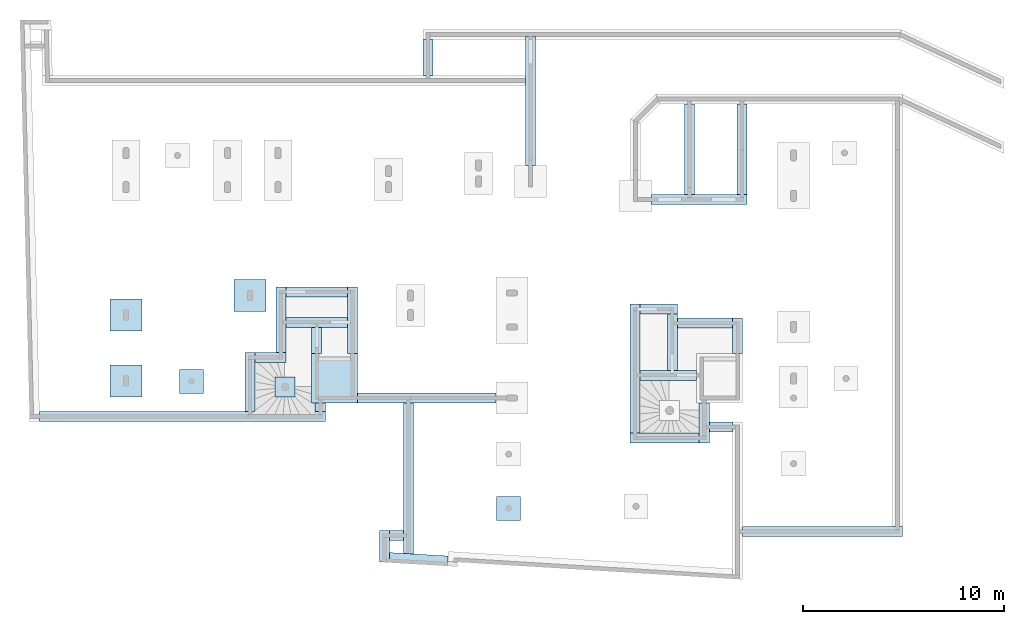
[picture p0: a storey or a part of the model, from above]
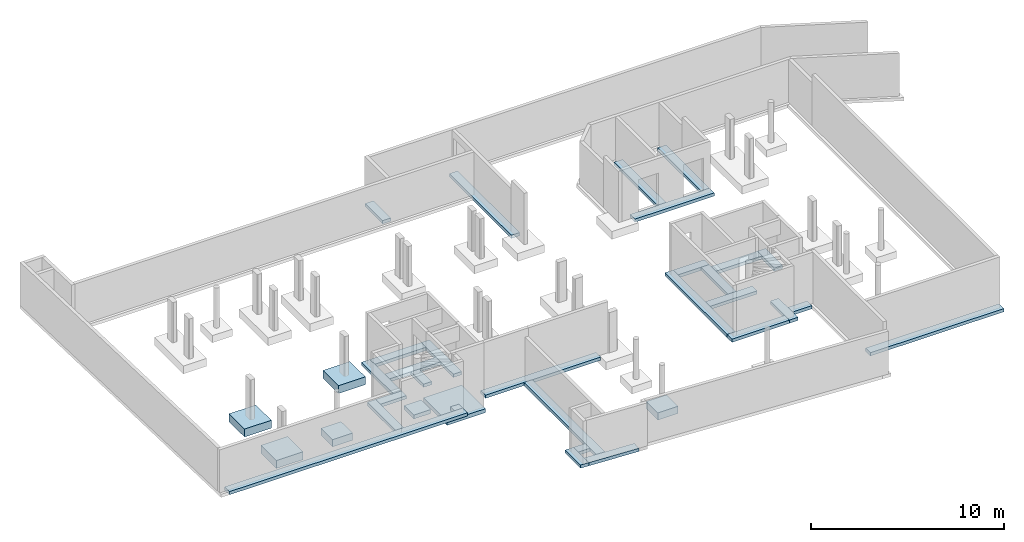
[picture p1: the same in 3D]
Properties of the parts of a building model (IFC2X3)

# File
Description: ViewDefinition [CoordinationView_V2.0]
File name: D:\Documents\Cours 2016-2017\dossier bac pro\sous sol.ifc
Time: 2017-04-04T10:15:29
Organization: Nemetschek AG, Konrad-Zuse-Platz 1, 81829 Munich / Germany
Written by: The EXPRESS Data Manager Version 5.02.0110.b05 : 16 Jul 2014
Made in: Allplan 2016.1 29.11.2016 - 13:12:12

# IfcBuildingStorey, Sous-sol
In: Bâtiment
Elevation: -3300 mm

# IfcColumn (33)
In: Sous-sol
Material: <Unnamed Material>
Allplan Attributes - Catégorie de transformation: Nouvelle construction; Unité: m; Métier: Béton et béton armé
Name | Id_élt_Allmétré | NOI_UUID
<Unnamed Element> | 0022Pot0000001171 | a5af95d6-19c8-4933-9c63-25be082ca570--1171
<Unnamed Element> | 0022Pot0000001170 | a5af95d6-19c8-4933-9c63-25be082ca570--1170
<Unnamed Element> | 0022Pot0000001088 | a5af95d6-19c8-4933-9c63-25be082ca570--1088
<Unnamed Element> | 0022Pot0000001085 | a5af95d6-19c8-4933-9c63-25be082ca570--1085
<Unnamed Element> | 0022Pot0000001082 | a5af95d6-19c8-4933-9c63-25be082ca570--1082
<Unnamed Element> | 0022Pot0000001079 | a5af95d6-19c8-4933-9c63-25be082ca570--1079
<Unnamed Element> | 0022Pot0000001076 | a5af95d6-19c8-4933-9c63-25be082ca570--1076
<Unnamed Element> | 0022Pot0000001073 | a5af95d6-19c8-4933-9c63-25be082ca570--1073
<Unnamed Element> | 0022Pot0000001072 | a5af95d6-19c8-4933-9c63-25be082ca570--1072
<Unnamed Element> | 0022Pot0000001071 | a5af95d6-19c8-4933-9c63-25be082ca570--1071
<Unnamed Element> | 0022Pot0000001066 | a5af95d6-19c8-4933-9c63-25be082ca570--1066
<Unnamed Element> | 0022Pot0000001065 | a5af95d6-19c8-4933-9c63-25be082ca570--1065
<Unnamed Element> | 0022Pot0000001064 | a5af95d6-19c8-4933-9c63-25be082ca570--1064
<Unnamed Element> | 0022Pot0000001063 | a5af95d6-19c8-4933-9c63-25be082ca570--1063
<Unnamed Element> | 0022Pot0000001062 | a5af95d6-19c8-4933-9c63-25be082ca570--1062
<Unnamed Element> | 0022Pot0000001061 | a5af95d6-19c8-4933-9c63-25be082ca570--1061
<Unnamed Element> | 0022Pot0000001060 | a5af95d6-19c8-4933-9c63-25be082ca570--1060
<Unnamed Element> | 0022Pot0000001059 | a5af95d6-19c8-4933-9c63-25be082ca570--1059
<Unnamed Element> | 0022Pot0000001058 | a5af95d6-19c8-4933-9c63-25be082ca570--1058
<Unnamed Element> | 0022Pot0000001057 | a5af95d6-19c8-4933-9c63-25be082ca570--1057
<Unnamed Element> | 0022Pot0000001056 | a5af95d6-19c8-4933-9c63-25be082ca570--1056
<Unnamed Element> | 0022Pot0000001055 | a5af95d6-19c8-4933-9c63-25be082ca570--1055
<Unnamed Element> | 0022Pot0000001054 | a5af95d6-19c8-4933-9c63-25be082ca570--1054
<Unnamed Element> | 0022Pot0000001053 | a5af95d6-19c8-4933-9c63-25be082ca570--1053
<Unnamed Element> | 0022Pot0000001052 | a5af95d6-19c8-4933-9c63-25be082ca570--1052
<Unnamed Element> | 0022Pot0000001051 | a5af95d6-19c8-4933-9c63-25be082ca570--1051
<Unnamed Element> | 0022Pot0000001050 | a5af95d6-19c8-4933-9c63-25be082ca570--1050
<Unnamed Element> | 0022Pot0000001049 | a5af95d6-19c8-4933-9c63-25be082ca570--1049
<Unnamed Element> | 0022Pot0000001048 | a5af95d6-19c8-4933-9c63-25be082ca570--1048
<Unnamed Element> | 0022Pot0000001045 | a5af95d6-19c8-4933-9c63-25be082ca570--1045
<Unnamed Element> | 0022Pot0000003037 | a5af95d6-19c8-4933-9c63-25be082ca570--3037
<Unnamed Element> | 0022Pot0000003062 | a5af95d6-19c8-4933-9c63-25be082ca570--3062
<Unnamed Element> | 0022Pot0000003086 | a5af95d6-19c8-4933-9c63-25be082ca570--3086

# IfcFooting (72)
In: Sous-sol
Material: <Unnamed Material>
Allplan Attributes - Catégorie de transformation: Nouvelle construction
Name | Id_élt_Allmétré | Unité | NOI_UUID | PredefinedType
<Unnamed Element> | 0022SeI0000001096 | m³ | a5af95d6-19c8-4933-9c63-25be082ca570--1096
<Unnamed Element> | 0022SeI0000001104 | m³ | a5af95d6-19c8-4933-9c63-25be082ca570--1104
<Unnamed Element> | 0022SeI0000001106 | m³ | a5af95d6-19c8-4933-9c63-25be082ca570--1106
<Unnamed Element> | 0022SeI0000001108 | m³ | a5af95d6-19c8-4933-9c63-25be082ca570--1108
<Unnamed Element> | 0022SeI0000001117 | m³ | a5af95d6-19c8-4933-9c63-25be082ca570--1117
<Unnamed Element> | 0022SeI0000001125 | m³ | a5af95d6-19c8-4933-9c63-25be082ca570--1125
<Unnamed Element> | 0022SeI0000001126 | m³ | a5af95d6-19c8-4933-9c63-25be082ca570--1126
<Unnamed Element> | 0022SeI0000001127 | m³ | a5af95d6-19c8-4933-9c63-25be082ca570--1127
<Unnamed Element> | 0022SeI0000001135 | m³ | a5af95d6-19c8-4933-9c63-25be082ca570--1135
<Unnamed Element> | 0022SeI0000001136 | m³ | a5af95d6-19c8-4933-9c63-25be082ca570--1136
<Unnamed Element> | 0022SeI0000001137 | m³ | a5af95d6-19c8-4933-9c63-25be082ca570--1137
<Unnamed Element> | 0022SeI0000001138 | m³ | a5af95d6-19c8-4933-9c63-25be082ca570--1138
<Unnamed Element> | 0022SeI0000001107 | m³ | a5af95d6-19c8-4933-9c63-25be082ca570--1107
<Unnamed Element> | 0022SeI0000001147 | m³ | a5af95d6-19c8-4933-9c63-25be082ca570--1147
<Unnamed Element> | 0022SeI0000001148 | m³ | a5af95d6-19c8-4933-9c63-25be082ca570--1148
<Unnamed Element> | 0022SeI0000001149 | m³ | a5af95d6-19c8-4933-9c63-25be082ca570--1149
<Unnamed Element> | 0022SeI0000001150 | m³ | a5af95d6-19c8-4933-9c63-25be082ca570--1150
<Unnamed Element> | 0022SeI0000001151 | m³ | a5af95d6-19c8-4933-9c63-25be082ca570--1151
<Unnamed Element> | 0022SeI0000001152 | m³ | a5af95d6-19c8-4933-9c63-25be082ca570--1152
<Unnamed Element> | 0022SeI0000001153 | m³ | a5af95d6-19c8-4933-9c63-25be082ca570--1153
<Unnamed Element> | 0022SeI0000001154 | m³ | a5af95d6-19c8-4933-9c63-25be082ca570--1154
<Unnamed Element> | 0022SeI0000001155 | m³ | a5af95d6-19c8-4933-9c63-25be082ca570--1155
<Unnamed Element> | 0022SeI0000001172 | m³ | a5af95d6-19c8-4933-9c63-25be082ca570--1172
<Unnamed Element> | 0022SeI0000001182 | m³ | a5af95d6-19c8-4933-9c63-25be082ca570--1182
<Unnamed Element> | 0022SeI0000001183 | m³ | a5af95d6-19c8-4933-9c63-25be082ca570--1183
<Unnamed Element> | 0022SeF0000001484 | m³ | a5af95d6-19c8-4933-9c63-25be082ca570--1484 | STRIP_FOOTING
<Unnamed Element> | 0022SeF0000001908 | m³ | a5af95d6-19c8-4933-9c63-25be082ca570--1908 | STRIP_FOOTING
<Unnamed Element> | 0022SeF0000001926 | m³ | a5af95d6-19c8-4933-9c63-25be082ca570--1926 | STRIP_FOOTING
<Unnamed Element> | 0022SeF0000001776 | m³ | a5af95d6-19c8-4933-9c63-25be082ca570--1776 | STRIP_FOOTING
<Unnamed Element> | 0022SeF0000001761 | m³ | a5af95d6-19c8-4933-9c63-25be082ca570--1761 | STRIP_FOOTING
<Unnamed Element> | 0022SeF0000001765 | m³ | a5af95d6-19c8-4933-9c63-25be082ca570--1765 | STRIP_FOOTING
<Unnamed Element> | 0022SeF0000001983 | m³ | a5af95d6-19c8-4933-9c63-25be082ca570--1983 | STRIP_FOOTING
<Unnamed Element> | 0022SeF0000001684 | m³ | a5af95d6-19c8-4933-9c63-25be082ca570--1684 | STRIP_FOOTING
<Unnamed Element> | 0022SeF0000001894 | m³ | a5af95d6-19c8-4933-9c63-25be082ca570--1894 | STRIP_FOOTING
<Unnamed Element> | 0022SeF0000002163 | m³ | a5af95d6-19c8-4933-9c63-25be082ca570--2163 | STRIP_FOOTING
<Unnamed Element> | 0022SeF0000002172 | m³ | a5af95d6-19c8-4933-9c63-25be082ca570--2172 | STRIP_FOOTING
<Unnamed Element> | 0022Rad0000002350 | m² | a5af95d6-19c8-4933-9c63-25be082ca570--2350
<Unnamed Element> | 0022Rad0000002353 | m² | a5af95d6-19c8-4933-9c63-25be082ca570--2353
<Unnamed Element> | 0022SeF0000002139 | m³ | a5af95d6-19c8-4933-9c63-25be082ca570--2139 | STRIP_FOOTING
<Unnamed Element> | 0022SeF0000002156 | m³ | a5af95d6-19c8-4933-9c63-25be082ca570--2156 | STRIP_FOOTING
<Unnamed Element> | 0022SeF0000002149 | m³ | a5af95d6-19c8-4933-9c63-25be082ca570--2149 | STRIP_FOOTING
<Unnamed Element> | 0022SeF0000002184 | m³ | a5af95d6-19c8-4933-9c63-25be082ca570--2184 | STRIP_FOOTING
<Unnamed Element> | 0022SeF0000002135 | m³ | a5af95d6-19c8-4933-9c63-25be082ca570--2135 | STRIP_FOOTING
<Unnamed Element> | 0022SeF0000002122 | m³ | a5af95d6-19c8-4933-9c63-25be082ca570--2122 | STRIP_FOOTING
<Unnamed Element> | 0022SeF0000001665 | m³ | a5af95d6-19c8-4933-9c63-25be082ca570--1665 | STRIP_FOOTING
<Unnamed Element> | 0022SeF0000001672 | m³ | a5af95d6-19c8-4933-9c63-25be082ca570--1672 | STRIP_FOOTING
<Unnamed Element> | 0022SeF0000001730 | m³ | a5af95d6-19c8-4933-9c63-25be082ca570--1730 | STRIP_FOOTING
<Unnamed Element> | 0022SeF0000001410 | m³ | a5af95d6-19c8-4933-9c63-25be082ca570--1410 | STRIP_FOOTING
<Unnamed Element> | 0022SeF0000001420 | m³ | a5af95d6-19c8-4933-9c63-25be082ca570--1420 | STRIP_FOOTING
<Unnamed Element> | 0022SeF0000001472 | m³ | a5af95d6-19c8-4933-9c63-25be082ca570--1472 | STRIP_FOOTING
<Unnamed Element> | 0022SeF0000001448 | m³ | a5af95d6-19c8-4933-9c63-25be082ca570--1448 | STRIP_FOOTING
<Unnamed Element> | 0022SeF0000001460 | m³ | a5af95d6-19c8-4933-9c63-25be082ca570--1460 | STRIP_FOOTING
<Unnamed Element> | 0022SeF0000001406 | m³ | a5af95d6-19c8-4933-9c63-25be082ca570--1406 | STRIP_FOOTING
<Unnamed Element> | 0022SeF0000002000 | m³ | a5af95d6-19c8-4933-9c63-25be082ca570--2000 | STRIP_FOOTING
<Unnamed Element> | 0022SeF0000001957 | m³ | a5af95d6-19c8-4933-9c63-25be082ca570--1957 | STRIP_FOOTING
<Unnamed Element> | 0022SeF0000001737 | m³ | a5af95d6-19c8-4933-9c63-25be082ca570--1737 | STRIP_FOOTING
<Unnamed Element> | 0022SeF0000001996 | m³ | a5af95d6-19c8-4933-9c63-25be082ca570--1996 | STRIP_FOOTING
<Unnamed Element> | 0022SeF0000001964 | m³ | a5af95d6-19c8-4933-9c63-25be082ca570--1964 | STRIP_FOOTING
<Unnamed Element> | 0022SeF0000001749 | m³ | a5af95d6-19c8-4933-9c63-25be082ca570--1749 | STRIP_FOOTING
<Unnamed Element> | 0022SeF0000002013 | m³ | a5af95d6-19c8-4933-9c63-25be082ca570--2013 | STRIP_FOOTING
<Unnamed Element> | 0022SeF0000002053 | m³ | a5af95d6-19c8-4933-9c63-25be082ca570--2053 | STRIP_FOOTING
<Unnamed Element> | 0022SeF0000001708 | m³ | a5af95d6-19c8-4933-9c63-25be082ca570--1708 | STRIP_FOOTING
<Unnamed Element> | 0022SeF0000002041 | m³ | a5af95d6-19c8-4933-9c63-25be082ca570--2041 | STRIP_FOOTING
<Unnamed Element> | 0022SeF0000002083 | m³ | a5af95d6-19c8-4933-9c63-25be082ca570--2083 | STRIP_FOOTING
<Unnamed Element> | 0022SeF0000002029 | m³ | a5af95d6-19c8-4933-9c63-25be082ca570--2029 | STRIP_FOOTING
<Unnamed Element> | 0022SeF0000001696 | m³ | a5af95d6-19c8-4933-9c63-25be082ca570--1696 | STRIP_FOOTING
<Unnamed Element> | 0022SeF0000001812 | m³ | a5af95d6-19c8-4933-9c63-25be082ca570--1812 | STRIP_FOOTING
<Unnamed Element> | 0022SeF0000001800 | m³ | a5af95d6-19c8-4933-9c63-25be082ca570--1800 | STRIP_FOOTING
<Unnamed Element> | 0022SeF0000001788 | m³ | a5af95d6-19c8-4933-9c63-25be082ca570--1788 | STRIP_FOOTING
<Unnamed Element> | 0022SeF0000001819 | m³ | a5af95d6-19c8-4933-9c63-25be082ca570--1819 | STRIP_FOOTING
<Unnamed Element> | 0022SeF0000001870 | m³ | a5af95d6-19c8-4933-9c63-25be082ca570--1870 | STRIP_FOOTING
<Unnamed Element> | 0022SeI0000003094 | m³ | a5af95d6-19c8-4933-9c63-25be082ca570--3094

# IfcOpeningElement: Opening (12)
In: Sous-sol
Allplan Attributes - Object Layer Attributes #1, Catégorie de transformation: Nouvelle construction; Object Layer Attributes #1, Unité: m²; Object Layer Attributes #1, Métier: Béton et béton armé
Name | Object Layer Attributes #1, Id_élt_Allmétré | Object Layer Attributes #1, NOI_UUID
Baie de porte | 0022Por0000000967 | a5af95d6-19c8-4933-9c63-25be082ca570--967
Baie de porte | 0022Por0000000979 | a5af95d6-19c8-4933-9c63-25be082ca570--979
Baie de porte | 0022Por0000000943 | a5af95d6-19c8-4933-9c63-25be082ca570--943
Baie de porte | 0022Por0000000933 | a5af95d6-19c8-4933-9c63-25be082ca570--933
Baie de porte | 0022Por0000000953 | a5af95d6-19c8-4933-9c63-25be082ca570--953
Baie de porte | 0022Por0000001013 | a5af95d6-19c8-4933-9c63-25be082ca570--1013
Baie de porte | 0022Por0000001025 | a5af95d6-19c8-4933-9c63-25be082ca570--1025
Baie de porte | 0022Por0000001035 | a5af95d6-19c8-4933-9c63-25be082ca570--1035
Baie de porte | 0022Por0000000999 | a5af95d6-19c8-4933-9c63-25be082ca570--999
Baie de porte | 0022Por0000000989 | a5af95d6-19c8-4933-9c63-25be082ca570--989
Baie de porte | 0022Por0000002255 | a5af95d6-19c8-4933-9c63-25be082ca570--2255
Baie de porte | 0022Por0000003026 | a5af95d6-19c8-4933-9c63-25be082ca570--3026

# IfcSlab (6)
In: Sous-sol
PredefinedType: FLOOR; Material: <Unnamed Material> 130 mm
Allplan Attributes - Catégorie de transformation: Nouvelle construction; Unité: m²
Name | Id_élt_Allmétré | NOI_UUID
<Unnamed Element> | 0023Dal0000000005 | 96981e33-3a63-40da-b6a2-6a6739d5f932--5
<Unnamed Element> | 0023Dal0000000008 | 96981e33-3a63-40da-b6a2-6a6739d5f932--8
<Unnamed Element> | 0023Dal0000000026 | 96981e33-3a63-40da-b6a2-6a6739d5f932--26
<Unnamed Element> | 0023Dal0000000029 | 96981e33-3a63-40da-b6a2-6a6739d5f932--29
<Unnamed Element> | 0023Dal0000000032 | 96981e33-3a63-40da-b6a2-6a6739d5f932--32
<Unnamed Element> | 0023Dal0000000035 | 96981e33-3a63-40da-b6a2-6a6739d5f932--35

# IfcStair (2)
In: Sous-sol
Material: Escalier hélicoïdal
Pset_StairCommon - NumberOfRiser: 17; RiserHeight: 179.412 mm; TreadLength: 194.05 mm; NumberOfTreads: 17
Allplan Attributes - Unité: Qt; Matériau: Escalier hélicoïdal
Name | Id_élt_Allmétré | NOI_UUID
<Unnamed Element> | 0022Esc0000003039 | a5af95d6-19c8-4933-9c63-25be082ca570--3039
<Unnamed Element> | 0022Esc0000003087 | a5af95d6-19c8-4933-9c63-25be082ca570--3087

# IfcWallStandardCase (62)
In: Sous-sol
Allplan Attributes - Unité: Qt; Object Layer Attributes #1, Catégorie de transformation: Nouvelle construction; Object Layer Attributes #1, Unité: m²; Object Layer Attributes #1, Métier: Béton et béton armé
Name | Material | Id_élt_Allmétré | NOI_UUID | Object Layer Attributes #1, Id_élt_Allmétré | Object Layer Attributes #1, NOI_UUID
<Unnamed Element> | béton 200 mm | 0022HMu0000000030 | a5af95d6-19c8-4933-9c63-25be082ca570--30 | 0022Mu_0000000031 | a5af95d6-19c8-4933-9c63-25be082ca570--31
<Unnamed Element> | béton 200 mm | 0022HMu0000000042 | a5af95d6-19c8-4933-9c63-25be082ca570--42 | 0022Mu_0000000043 | a5af95d6-19c8-4933-9c63-25be082ca570--43
<Unnamed Element> | béton 200 mm | 0022HMu0000000054 | a5af95d6-19c8-4933-9c63-25be082ca570--54 | 0022Mu_0000000055 | a5af95d6-19c8-4933-9c63-25be082ca570--55
<Unnamed Element> | béton 200 mm | 0022HMu0000000065 | a5af95d6-19c8-4933-9c63-25be082ca570--65 | 0022Mu_0000000066 | a5af95d6-19c8-4933-9c63-25be082ca570--66
<Unnamed Element> | béton 200 mm | 0022HMu0000000078 | a5af95d6-19c8-4933-9c63-25be082ca570--78 | 0022Mu_0000000079 | a5af95d6-19c8-4933-9c63-25be082ca570--79
<Unnamed Element> | béton 200 mm | 0022HMu0000000089 | a5af95d6-19c8-4933-9c63-25be082ca570--89 | 0022Mu_0000000090 | a5af95d6-19c8-4933-9c63-25be082ca570--90
<Unnamed Element> | béton 200 mm | 0022HMu0000000101 | a5af95d6-19c8-4933-9c63-25be082ca570--101 | 0022Mu_0000000102 | a5af95d6-19c8-4933-9c63-25be082ca570--102
<Unnamed Element> | béton 200 mm | 0022HMu0000000114 | a5af95d6-19c8-4933-9c63-25be082ca570--114 | 0022Mu_0000000115 | a5af95d6-19c8-4933-9c63-25be082ca570--115
<Unnamed Element> | béton 200 mm | 0022HMu0000000137 | a5af95d6-19c8-4933-9c63-25be082ca570--137 | 0022Mu_0000000138 | a5af95d6-19c8-4933-9c63-25be082ca570--138
<Unnamed Element> | béton 180 mm | 0022HMu0000000186 | a5af95d6-19c8-4933-9c63-25be082ca570--186 | 0022Mu_0000000187 | a5af95d6-19c8-4933-9c63-25be082ca570--187
<Unnamed Element> | béton 180 mm | 0022HMu0000000196 | a5af95d6-19c8-4933-9c63-25be082ca570--196 | 0022Mu_0000000197 | a5af95d6-19c8-4933-9c63-25be082ca570--197
<Unnamed Element> | béton 180 mm | 0022HMu0000000208 | a5af95d6-19c8-4933-9c63-25be082ca570--208 | 0022Mu_0000000209 | a5af95d6-19c8-4933-9c63-25be082ca570--209
<Unnamed Element> | béton 200 mm | 0022HMu0000000219 | a5af95d6-19c8-4933-9c63-25be082ca570--219 | 0022Mu_0000000220 | a5af95d6-19c8-4933-9c63-25be082ca570--220
<Unnamed Element> | béton 200 mm | 0022HMu0000000230 | a5af95d6-19c8-4933-9c63-25be082ca570--230 | 0022Mu_0000000231 | a5af95d6-19c8-4933-9c63-25be082ca570--231
<Unnamed Element> | béton 200 mm | 0022HMu0000000272 | a5af95d6-19c8-4933-9c63-25be082ca570--272 | 0022Mu_0000000273 | a5af95d6-19c8-4933-9c63-25be082ca570--273
<Unnamed Element> | béton 200 mm | 0022HMu0000000293 | a5af95d6-19c8-4933-9c63-25be082ca570--293 | 0022Mu_0000000294 | a5af95d6-19c8-4933-9c63-25be082ca570--294
<Unnamed Element> | béton 200 mm | 0022HMu0000000306 | a5af95d6-19c8-4933-9c63-25be082ca570--306 | 0022Mu_0000000307 | a5af95d6-19c8-4933-9c63-25be082ca570--307
<Unnamed Element> | béton 200 mm | 0022HMu0000000330 | a5af95d6-19c8-4933-9c63-25be082ca570--330 | 0022Mu_0000000331 | a5af95d6-19c8-4933-9c63-25be082ca570--331
<Unnamed Element> | béton 200 mm | 0022HMu0000000371 | a5af95d6-19c8-4933-9c63-25be082ca570--371 | 0022Mu_0000000372 | a5af95d6-19c8-4933-9c63-25be082ca570--372
<Unnamed Element> | béton 180 mm | 0022HMu0000000380 | a5af95d6-19c8-4933-9c63-25be082ca570--380 | 0022Mu_0000000381 | a5af95d6-19c8-4933-9c63-25be082ca570--381
<Unnamed Element> | béton 200 mm | 0022HMu0000000387 | a5af95d6-19c8-4933-9c63-25be082ca570--387 | 0022Mu_0000000388 | a5af95d6-19c8-4933-9c63-25be082ca570--388
<Unnamed Element> | béton 180 mm | 0022HMu0000000468 | a5af95d6-19c8-4933-9c63-25be082ca570--468 | 0022Mu_0000000469 | a5af95d6-19c8-4933-9c63-25be082ca570--469
<Unnamed Element> | béton 180 mm | 0022HMu0000000499 | a5af95d6-19c8-4933-9c63-25be082ca570--499 | 0022Mu_0000000500 | a5af95d6-19c8-4933-9c63-25be082ca570--500
<Unnamed Element> | béton 200 mm | 0022HMu0000000513 | a5af95d6-19c8-4933-9c63-25be082ca570--513 | 0022Mu_0000000514 | a5af95d6-19c8-4933-9c63-25be082ca570--514
<Unnamed Element> | béton 200 mm | 0022HMu0000000527 | a5af95d6-19c8-4933-9c63-25be082ca570--527 | 0022Mu_0000000528 | a5af95d6-19c8-4933-9c63-25be082ca570--528
<Unnamed Element> | béton 200 mm | 0022HMu0000000538 | a5af95d6-19c8-4933-9c63-25be082ca570--538 | 0022Mu_0000000539 | a5af95d6-19c8-4933-9c63-25be082ca570--539
<Unnamed Element> | béton 200 mm | 0022HMu0000000712 | a5af95d6-19c8-4933-9c63-25be082ca570--712 | 0022Mu_0000000713 | a5af95d6-19c8-4933-9c63-25be082ca570--713
<Unnamed Element> | béton 200 mm | 0022HMu0000000727 | a5af95d6-19c8-4933-9c63-25be082ca570--727 | 0022Mu_0000000728 | a5af95d6-19c8-4933-9c63-25be082ca570--728
<Unnamed Element> | béton 200 mm | 0022HMu0000000740 | a5af95d6-19c8-4933-9c63-25be082ca570--740 | 0022Mu_0000000741 | a5af95d6-19c8-4933-9c63-25be082ca570--741
<Unnamed Element> | béton 200 mm | 0022HMu0000000753 | a5af95d6-19c8-4933-9c63-25be082ca570--753 | 0022Mu_0000000754 | a5af95d6-19c8-4933-9c63-25be082ca570--754
<Unnamed Element> | béton 200 mm | 0022HMu0000000778 | a5af95d6-19c8-4933-9c63-25be082ca570--778 | 0022Mu_0000000779 | a5af95d6-19c8-4933-9c63-25be082ca570--779
<Unnamed Element> | béton 200 mm | 0022HMu0000000788 | a5af95d6-19c8-4933-9c63-25be082ca570--788 | 0022Mu_0000000789 | a5af95d6-19c8-4933-9c63-25be082ca570--789
<Unnamed Element> | béton 200 mm | 0022HMu0000000801 | a5af95d6-19c8-4933-9c63-25be082ca570--801 | 0022Mu_0000000802 | a5af95d6-19c8-4933-9c63-25be082ca570--802
<Unnamed Element> | béton 200 mm | 0022HMu0000000815 | a5af95d6-19c8-4933-9c63-25be082ca570--815 | 0022Mu_0000000816 | a5af95d6-19c8-4933-9c63-25be082ca570--816
<Unnamed Element> | béton 200 mm | 0022HMu0000000895 | a5af95d6-19c8-4933-9c63-25be082ca570--895 | 0022Mu_0000000896 | a5af95d6-19c8-4933-9c63-25be082ca570--896
<Unnamed Element> | béton 200 mm | 0022HMu0000000018 | a5af95d6-19c8-4933-9c63-25be082ca570--18 | 0022Mu_0000000019 | a5af95d6-19c8-4933-9c63-25be082ca570--19
<Unnamed Element> | béton 200 mm | 0022HMu0000001187 | a5af95d6-19c8-4933-9c63-25be082ca570--1187 | 0022Mu_0000001189 | a5af95d6-19c8-4933-9c63-25be082ca570--1189
<Unnamed Element> | béton 180 mm | 0022HMu0000000461 | a5af95d6-19c8-4933-9c63-25be082ca570--461 | 0022Mu_0000000462 | a5af95d6-19c8-4933-9c63-25be082ca570--462
<Unnamed Element> | béton 180 mm | 0022HMu0000001253 | a5af95d6-19c8-4933-9c63-25be082ca570--1253 | 0022Mu_0000001260 | a5af95d6-19c8-4933-9c63-25be082ca570--1260
<Unnamed Element> | béton 180 mm | 0022HMu0000000487 | a5af95d6-19c8-4933-9c63-25be082ca570--487 | 0022Mu_0000000488 | a5af95d6-19c8-4933-9c63-25be082ca570--488
<Unnamed Element> | béton 180 mm | 0022HMu0000001285 | a5af95d6-19c8-4933-9c63-25be082ca570--1285 | 0022Mu_0000001287 | a5af95d6-19c8-4933-9c63-25be082ca570--1287
<Unnamed Element> | béton 200 mm | 0022HMu0000000007 | a5af95d6-19c8-4933-9c63-25be082ca570--7 | 0022Mu_0000000008 | a5af95d6-19c8-4933-9c63-25be082ca570--8
<Unnamed Element> | béton 200 mm | 0022HMu0000001308 | a5af95d6-19c8-4933-9c63-25be082ca570--1308 | 0022Mu_0000001311 | a5af95d6-19c8-4933-9c63-25be082ca570--1311
<Unnamed Element> | béton 200 mm | 0022HMu0000000687 | a5af95d6-19c8-4933-9c63-25be082ca570--687 | 0022Mu_0000000688 | a5af95d6-19c8-4933-9c63-25be082ca570--688 | Allplan Attributes - Object Layer Attributes #1, Matériau: béton
<Unnamed Element> | béton 180 mm | 0022HMu0000000149 | a5af95d6-19c8-4933-9c63-25be082ca570--149 | 0022Mu_0000000150 | a5af95d6-19c8-4933-9c63-25be082ca570--150
<Unnamed Element> | béton 180 mm | 0022HMu0000002227 | a5af95d6-19c8-4933-9c63-25be082ca570--2227 | 0022Mu_0000002229 | a5af95d6-19c8-4933-9c63-25be082ca570--2229
<Unnamed Element> | béton 180 mm | 0022HMu0000000416 | a5af95d6-19c8-4933-9c63-25be082ca570--416 | 0022Mu_0000000417 | a5af95d6-19c8-4933-9c63-25be082ca570--417
<Unnamed Element> | béton 180 mm | 0022HMu0000002252 | a5af95d6-19c8-4933-9c63-25be082ca570--2252 | 0022Mu_0000002257 | a5af95d6-19c8-4933-9c63-25be082ca570--2257
<Unnamed Element> | béton 200 mm | 0022HMu0000000125 | a5af95d6-19c8-4933-9c63-25be082ca570--125 | 0022Mu_0000000126 | a5af95d6-19c8-4933-9c63-25be082ca570--126
<Unnamed Element> | béton 200 mm | 0022HMu0000002288 | a5af95d6-19c8-4933-9c63-25be082ca570--2288 | 0022Mu_0000002291 | a5af95d6-19c8-4933-9c63-25be082ca570--2291
<Unnamed Element> | béton 200 mm | 0022HMu0000000002 | a5af95d6-19c8-4933-9c63-25be082ca570--2 | 0022Mu_0000000003 | a5af95d6-19c8-4933-9c63-25be082ca570--3
<Unnamed Element> | béton 200 mm | 0022HMu0000002358 | a5af95d6-19c8-4933-9c63-25be082ca570--2358 | 0022Mu_0000002360 | a5af95d6-19c8-4933-9c63-25be082ca570--2360
<Unnamed Element> | béton 200 mm | 0022HMu0000002397 | a5af95d6-19c8-4933-9c63-25be082ca570--2397 | 0022Mu_0000002398 | a5af95d6-19c8-4933-9c63-25be082ca570--2398
<Unnamed Element> | béton 200 mm | 0022HMu0000000911 | a5af95d6-19c8-4933-9c63-25be082ca570--911 | 0022Mu_0000000912 | a5af95d6-19c8-4933-9c63-25be082ca570--912 | Allplan Attributes - Object Layer Attributes #1, Matériau: béton
<Unnamed Element> | béton 200 mm | 0022HMu0000000318 | a5af95d6-19c8-4933-9c63-25be082ca570--318 | 0022Mu_0000000319 | a5af95d6-19c8-4933-9c63-25be082ca570--319
<Unnamed Element> | béton 200 mm | 0022HMu0000002420 | a5af95d6-19c8-4933-9c63-25be082ca570--2420 | 0022Mu_0000002422 | a5af95d6-19c8-4933-9c63-25be082ca570--2422
<Unnamed Element> | béton 200 mm | 0022HMu0000000356 | a5af95d6-19c8-4933-9c63-25be082ca570--356 | 0022Mu_0000000357 | a5af95d6-19c8-4933-9c63-25be082ca570--357
<Unnamed Element> | béton 200 mm | 0022HMu0000002455 | a5af95d6-19c8-4933-9c63-25be082ca570--2455 | 0022Mu_0000002457 | a5af95d6-19c8-4933-9c63-25be082ca570--2457
<Unnamed Element> | béton 200 mm | 0022HMu0000000340 | a5af95d6-19c8-4933-9c63-25be082ca570--340 | 0022Mu_0000000341 | a5af95d6-19c8-4933-9c63-25be082ca570--341
<Unnamed Element> | béton 200 mm | 0022HMu0000002470 | a5af95d6-19c8-4933-9c63-25be082ca570--2470 | 0022Mu_0000002473 | a5af95d6-19c8-4933-9c63-25be082ca570--2473
<Unnamed Element> | béton 200 mm | 0022HMu0000002490 | a5af95d6-19c8-4933-9c63-25be082ca570--2490 | 0022Mu_0000002493 | a5af95d6-19c8-4933-9c63-25be082ca570--2493
<Unnamed Element> | béton 200 mm | 0022HMu0000000282 | a5af95d6-19c8-4933-9c63-25be082ca570--282 | 0022Mu_0000000283 | a5af95d6-19c8-4933-9c63-25be082ca570--283 | Allplan Attributes - Object Layer Attributes #1, Matériau: béton
